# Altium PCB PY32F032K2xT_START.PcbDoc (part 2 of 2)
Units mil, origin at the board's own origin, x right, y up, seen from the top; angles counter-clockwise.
Board outline 1771.65 x 3929.06 mil, 2 copper layers (Top Layer, Bottom Layer), stack 21 mil thick; 140 components, 131 nets, 499 pads, 343 vias.
Unrouted connection lines stored in the file: 5.

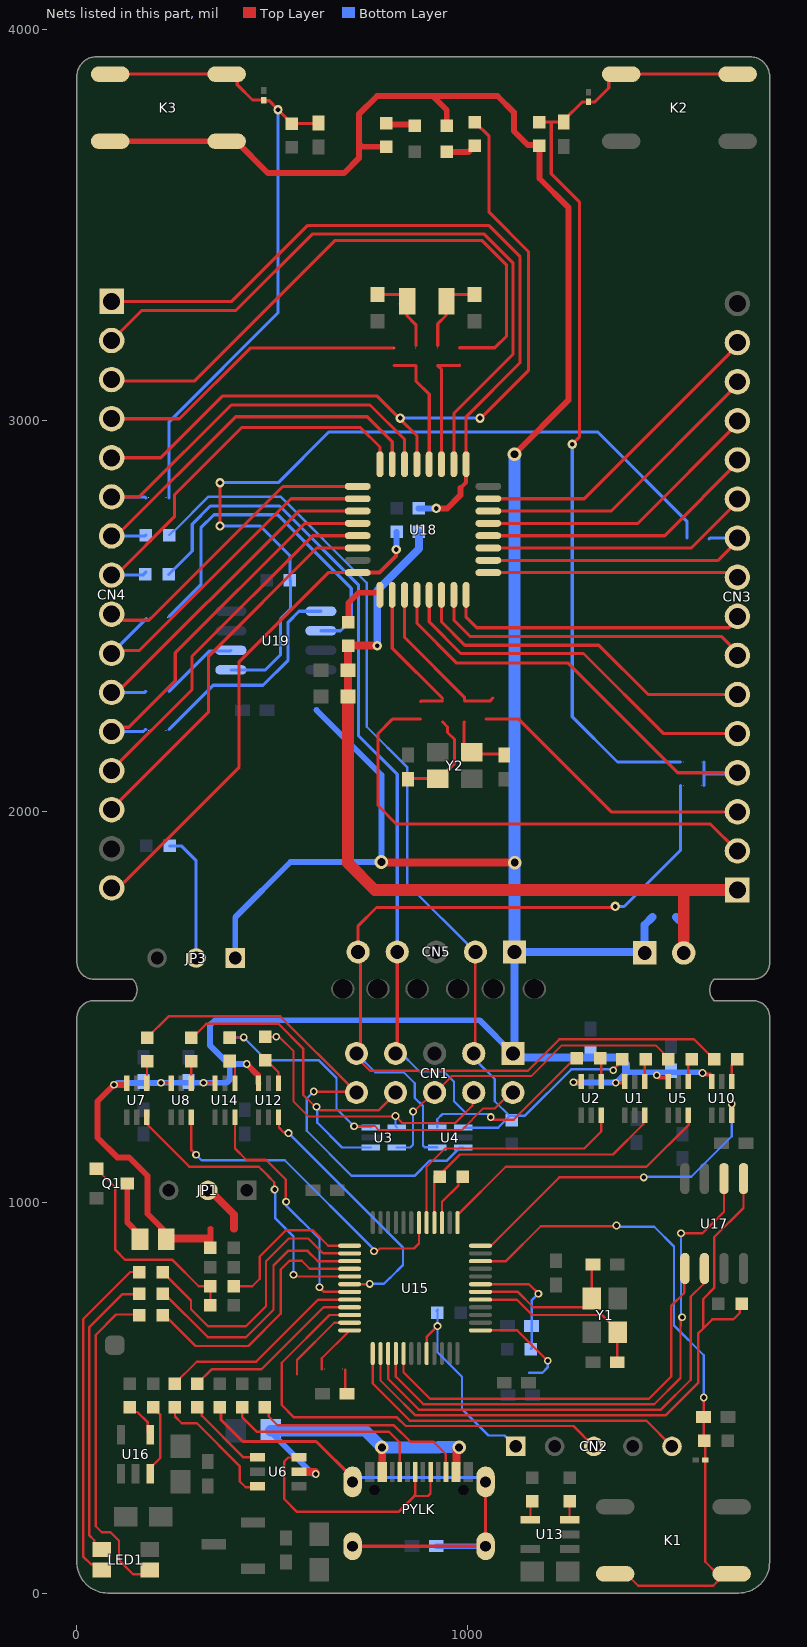
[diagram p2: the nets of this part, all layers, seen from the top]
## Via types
v1: diameter 24, hole 12, Top Layer to Bottom Layer, tented both sides, 162 vias
v2: diameter 19.68, hole 11.81, Top Layer to Bottom Layer, tented both sides, 128 vias
v3: diameter 19.68, hole 11.81, Top Layer to Bottom Layer, 38 vias
v4: diameter 35, hole 20, Top Layer to Bottom Layer, tented both sides, 11 vias
v5: diameter 30, hole 15, Top Layer to Bottom Layer, tented both sides, 2 vias
v6: diameter 40, hole 20, Top Layer to Bottom Layer, tented both sides, 2 vias

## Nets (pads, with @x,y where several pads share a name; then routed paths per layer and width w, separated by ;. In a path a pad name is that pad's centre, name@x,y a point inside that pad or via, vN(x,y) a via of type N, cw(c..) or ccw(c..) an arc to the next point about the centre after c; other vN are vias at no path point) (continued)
L_USB_CN_DP: PYLK.A6 PYLK.B6 U6.6 | length 662.8
  Top Layer w6: U6.6@568.15,347.4 567.26,346.51 540.39,346.51 530.35,336.47 530.35,240.4 563.22,207.53 822.27,207.53 863.1,248.36 865.36,250.62 PYLK.A6@865.36,309.89 ; 863.46,248 898,248 904.31,254.31 PYLK.B6@904.31,309.48
LED_BLUE: R9.2 U15.28 | length 675.2
  Top Layer w6: R9.2@220,710 225.04,710 303.26,631.77 438.53,631.77 521.33,714.58 521.33,827.41 543.92,850 575,850 595.79,829.21 U15.28@697.68,829.21
LED_GREEN: R6.2 U15.26 | length 724.3
  Top Layer w6: R6.2@220,820 291.82,748.18 291.82,725.67 335.36,682.13 432.27,682.13 483.48,733.34 483.48,848.48 541.75,906.75 591.91,906.75 630.07,868.58 U15.26@697.68,868.58
LED_RED: R4.2 U15.27 | length 692.2
  Top Layer w6: R4.2@220,765 224.07,765 335.03,654.04 432.13,654.04 502.68,724.59 502.68,837.68 540,875 590,875 616.1,848.9 U15.27@697.68,848.9
MCU_RST: CN3.4 R50.2 R57.2 U18.4 | length 1217.7
  Top Layer w8: U18.4@869.69,2558.46 869.69,2480.19 971.65,2378.23 1256.77,2378.23 1537,2098 CN3.4@1697,2098
  Bottom Layer w8: 1604,2065.5 1604,2095.38 ; 1604,2125.25 1604,2095.38 ; CN3.4@1697,2098 1694.38,2095.38 1604,2095.38
NetC1_2: C1.2 PYLK.1 PYLK.2 PYLK.3 PYLK.4 R8.1 | length 1421.6
  Top Layer w8: R8.1@365,475 368.29,471.71 368.29,443.87 424.64,387.52 611.97,387.52 705.12,294.37 PYLK.1@705.12,284.29 ; PYLK.3@705.12,119.73 PYLK.4@1045.28,119.73 PYLK.2@1045.28,284.29
  Bottom Layer w8: PYLK.1@716.04,295.21 PYLK.2@1034.36,295.21 ; C1.2@919,120 C1.2@919.27,119.73
  Bottom Layer w15: C1.2@919.27,119.73 PYLK.4@1045.28,119.73
  Bottom Layer w20: PYLK.1@705.12,284.29 PYLK.1@716.04,295.21 ; PYLK.2@1034.36,295.21 PYLK.2@1045.28,284.29
NetC17_2: C17.2 R31.2 | length 64.1
  Top Layer w6: 686.21,571.75 686.21,513.88 C17.2@690.59,509.5
NetC29_2: C29.2 K2.1 K2.2 R49.2 R50.1 U20.1 | length 2453.3
  Top Layer w8: R49.2@1182.49,3761.8 1182.7,3762 R49.2@1183,3762 C29.2@1245,3762 ; 1213.34,3761.8 1213.34,3629.85 1285.19,3558 1285.19,2956.19 v1(1267,2938) ; C29.2@1244.19,3765.19 1292.59,3813.59 1324.59,3813.59 1360.13,3849.13 1360.13,3870.21 1374.63,3884.7 K2.1@1392,3884.7 K2.2@1690,3884.7
  Bottom Layer w8: v1(1267,2938) 1267,2241 1382.75,2125.25 1544,2125.25
NetC30_2: C30.2 R51.1 Y2.3 | length 254.5
  Top Layer w8: C30.2@847.03,2081.4 848.56,2082.93 Y2.3@922.72,2082.93 926.65,2082.93 966.03,2122.31 966.03,2182.97 948,2201 948,2215.05 935.03,2228.03
NetC31_1: C31.1 R52.2 Y3.2 | length 182.1
  Top Layer w8: C31.1@769,3321.5 Y3.2@828.14,3321.5 ; Y3.2@827.14,3297.5 843.81,3280.83 843.81,3280 843.81,3267.21 867,3244.02 867,3191
NetC32_2: C32.2 R53.2 Y3.1 | length 191.1
  Top Layer w8: 923,3191 923,3246.01 944.2,3267.21 944.2,3280 Y3.1@953.94,3289.75 ; Y3.1@945.2,3304 945.2,3304.83 961.87,3321.5 C32.2@1017,3321.5
NetC33_2: C33.2 R54.1 Y2.1 | length 173.1
  Top Layer w8: 991.03,2228.03 989.84,2226.84 989.84,2169.36 1013.43,2145.77 1090.65,2145.77 C33.2@1093.03,2143.4
NetC34_2: C34.2 K3.3 K3.4 R59.1 R60.2 U21.1 | length 1703.1
  Top Layer w8: K3.4@85,3884.7 K3.3@383,3884.7 395.51,3884.7 410,3870.21 410,3857.7 449.24,3818.46 477.83,3818.46 479.74,3816.54 491.81,3816.54 v1(514.4,3793.95) 537,3771.35 537,3769.98 R60.2@549,3757.98 616.09,3757.98 C34.2@618,3759.89
  Bottom Layer w8: 235.99,2800.6 235.99,2995.9 514.4,3274.31 v1(514.4,3793.95)
NetCN3_2: CN3.2 R61.2 | length 1275.6
  Top Layer w8: R61.2@878.97,2234.97 806.97,2234.97 770,2198 770,2014 817,1967 1620.29,1967 CN3.2@1689.29,1898
NetCN3_3: CN3.3 R62.2 | length 740.5
  Top Layer w8: R62.2@1046.97,2234.97 1130.03,2234.97 1367,1998 CN3.3@1689.29,1998
NetCN4_3: CN4.3 R63.2 | length 1500.5
  Top Layer w8: CN4.3@89,3103.44 93.02,3099.42 300.42,3099.42 660.54,3459.54 1035.37,3459.54 1099,3395.9 1099,3215.06 1068.97,3185.03 R63.2@979.03,3185.03
NetCN4_4: CN4.4 R64.2 | length 796.8
  Top Layer w8: CN4.4@89,3003.44 262.44,3003.44 443.03,3184.03 R64.2@811.03,3184.03
NetJP3_2: JP3.2 R48.1 | length 332.8
  Bottom Layer w8: R48.1@237,1911 267.28,1911 305,1873.28 JP3.2@305,1624.13
NetLED1_2: LED1.2 R9.1 | length 846.1
  Top Layer w6: R9.1@160,710 157.67,712.33 100.33,712.33 48,660 48,171 63.8,155.2 85.86,155.2 107.53,133.53 107.53,84.16 143.82,47.87 175.08,47.87 LED1.2@186.02,58.82
NetLED1_3: LED1.3 R6.1 | length 884.3
  Top Layer w6: LED1.3@44.28,58.52 LED1.3@58.98,43.82 ; LED1.3@63.98,58.82 49.28,73.52 36.09,73.52 16,93.61 16,700.34 136.59,820.93 159.07,820.93 R6.1@160,820
NetLED1_4: LED1.4 R4.1 | length 755.1
  Top Layer w6: LED1.4@56.66,98.5 44.36,110.81 44.36,134.74 32,147.09 32,680.34 115.39,763.73 158.73,763.73 R4.1@160,765
NetLED_PA11_2: LED_PA11.2 R58.1 | length 78.7
  Top Layer w15: LED_PA11.2@946,3685.89 1001.89,3685.89 R58.1@1018,3702
NetLED_VDD*_1: LED_VDD*.1 R40.1 | length 75.5
  Top Layer w15: R40.1@791,3759 794,3756 861,3756 LED_VDD*.1@864,3753
NetPYLK_A5: PYLK.A5 R1.2 | length 530.3
  Top Layer w6: R1.2@422.49,474.99 422.49,449.82 459.51,412.79 797.58,412.79 825.99,384.38 PYLK.A5@825.99,309.89
NetPYLK_B5: PYLK.B5 R3.1 | length 566
  Top Layer w6: R3.1@480,475 490.31,464.69 490.31,452.34 513.85,428.8 811.11,428.8 852.66,387.24 911.55,387.24 943.17,355.62 943.17,310.82 PYLK.B5@944.1,309.89
NetQ1_1: Q1.1 R19.1 R20.2 | length 559
  Top Layer w6: Q1.1@50,1084.8 51.97,1084.8 63.72,1073.06 63.72,1071.23 98.46,1036.49 98.46,877.34 123.86,851.94 244.45,851.94 311.61,784.78 R19.1@341.53,784.78 ; R20.2@341.52,735.88 R19.1@341.52,784.77
NetQ1_3: Q1.3 R15.1 | length 166.5
  Top Layer w6: Q1.3@125.49,1044.15 Q1.3@128.74,1047.4 ; R15.1@161.54,905 R15.1@161.54,910.91
  Top Layer w15: Q1.3@128.74,1047.4 128.74,948.28 161.54,915.49 R15.1@161.54,905
NetR2_1: R2.1 U1.4 | length 57.9
  Top Layer w6: U1.4@1452.23,1308.31 1452.23,1362.02 R2.1@1455.21,1365
NetR7_1: R7.1 U2.4 | length 57.8
  Top Layer w6: R7.1@1338.06,1365 1340.8,1362.27 U2.4@1340.8,1308.31
NetR10_1: R10.1 U5.4 | length 60.3
  Top Layer w6: U5.4@1563.66,1308.31 1563.66,1356.3 R10.1@1572.35,1365
NetR11_1: R11.1 U6.3 | length 332.9
  Top Layer w6: R11.1@250,475 250.77,474.23 250.77,451.69 268.41,434.05 306.8,434.05 416.24,324.61 416.24,285.87 431.63,270.48 459.74,270.48 U6.3@461.53,272.28
NetR12_1: R12.1 U6.1 | length 227.7
  Top Layer w6: R12.1@308.75,480 319.15,469.6 319.15,453.68 426,346.83 U6.1@471.97,346.83
NetR13_1: R13.1 U7.4 | length 59
  Top Layer w6: R13.1@173.55,1360 179.14,1354.41 U7.4@179.14,1303.31
NetR14_1: R14.1 U8.4 | length 60.8
  Top Layer w6: R14.1@280.94,1360.02 R14.1@290.82,1350.14 ; U8.4@292.86,1303.31 R14.1@292.86,1350.12
NetR18_1: R18.1 U10.4 | length 62.7
  Top Layer w6: U10.4@1675.08,1308.31 1675.08,1350.59 R18.1@1689.49,1365
NetR22_1: R22.1 U12.4 | length 75.3
  Top Layer w6: R22.1@481.63,1362.11 485.62,1362.11 515.71,1332.03 U12.4@515.71,1303.31
NetR24_2: R24.2 U13.4 | length 49.6
  Top Layer w6: U13.4@1160,187.5 1160,230 R24.2@1165,235
NetR25_2: R25.2 U13.3 | length 47.5
  Top Layer w6: U13.3@1260,187.5 R25.2@1260,235
NetR26_1: R26.1 U14.4 | length 62.8
  Top Layer w6: R26.1@391.2,1360.7 404.28,1347.62 U14.4@404.28,1303.31
NetR27_2: R27.2 U15.1 | length 273.6
  Top Layer w6: U15.1@1032.32,671.73 1126.27,671.73 v3(1204,594)
  Bottom Layer w6: R27.2@1157.03,563.03 1190.03,563.03 1204,577 v3(1204,594)
NetR29_2: R29.2 U16.4 | length 96.1
  Top Layer w6: R29.2@135,475 147,463 154.44,463 181.5,435.94 181.5,411 U16.4@187.5,405
NetR30_2: R30.2 U16.3 | length 188.5
  Top Layer w6: U16.3@187.5,305 187.5,320 213.56,346.06 213.56,455.68 207,462.24 207,463 R30.2@195,475
NetR31_1: R31.1 U15.36 | length 129.6
  Top Layer w6: 626.21,571.75 626.21,600.26 U15.36@697.68,671.73
NetR33_1: R33.1 U15.35 | length 210.5
  Top Layer w6: R33.1@563,559.75 563,596 658.42,691.42 U15.35@697.68,691.42
NetR41_2: R41.2 U18.1 | length 141.2
  Top Layer w15: R41.2@694,2483 694,2532 720.46,2558.46 U18.1@775.19,2558.46
NetR43_1: R43.1 R44.2 U19.1 | length 2112.9
  Top Layer w8: v1(366,2729) v1(366,2840)
  Bottom Layer w8: v1(366,2729) 468.67,2729 545,2652.67 R43.1@545,2590 545.88,2589.12 545.88,2516.48 520.91,2491.51 520.91,2399.5 482.41,2361 U19.1@394,2361 ; v1(366,2840) 515,2840 644.46,2969.46 1332.02,2969.46 1559.97,2741.51 1559.97,2698.97
NetR45_2: R45.2 U19.2 | length 201.4
  Bottom Layer w8: 235.99,2305.99 339.55,2409.55 392.56,2409.55 U19.2@394,2411
NetR46_1: R46.1 U19.6 | length 906.3
  Bottom Layer w8: 236,2498 317,2579 317,2724.11 350.76,2757.86 513.27,2757.86 701.55,2569.58 701.55,2488.36 674.19,2461 U19.6@624,2461
NetR47_1: R47.1 U19.5 | length 570
  Bottom Layer w8: 236,2209 348.82,2321.82 476.11,2321.82 540.16,2385.88 540.16,2483.09 568.08,2511 U19.5@624,2511
OSC32IN: R52.1 R64.1 U18.20 | length 328.1
  Top Layer w8: R64.1@811,3139.25 R52.1@867,3139.25 867,3100 901.09,3065.91 U18.20@901.09,2881.26
OSC32OUT: R53.1 R63.1 U18.19 | length 318.4
  Top Layer w8: U18.19@932.59,2881.26 932.59,3129.66 R53.1@923,3139.25 978,3139.25 R63.1@979,3140.25
OSCIN: R51.2 R61.1 U18.2 | length 380.2
  Top Layer w8: U18.2@806.69,2558.46 806.69,2416.36 935.03,2288.03 ; R61.1@879,2279.75 880.31,2281.05 R51.2@935.05,2281.05
OSCOUT: R54.2 R62.1 U18.3 | length 417
  Top Layer w8: U18.3@838.19,2558.46 838.19,2443.81 991.05,2290.95 R54.2@991.05,2281.05 1056.05,2281.05 1064,2289
PA0: CN3.6 U18.6 | length 916
  Top Layer w8: U18.6@932.59,2558.46 932.59,2483.79 992.38,2424 1335,2424 1461,2298 CN3.6@1697,2298
PA1: CN3.7 U18.7 | length 840.3
  Top Layer w8: U18.7@964.09,2558.46 964.09,2488.64 1006.73,2446 1649,2446 CN3.7@1697,2398
PA2: CN3.8 U18.8 | length 787.4
  Top Layer w8: U18.8@995.59,2558.46 995.59,2495.58 1022.27,2468.91 1667.91,2468.91 CN3.8@1697,2498
PA3: CN3.9 U18.9 | length 647.3
  Top Layer w8: U18.9@1046.79,2609.66 1662.22,2609.66 1673.88,2598 CN3.9@1689.29,2598
PA4: CN3.10 R44.1 U18.10 | length 754.6
  Top Layer w8: U18.10@1046.79,2641.16 1640.16,2641.16 CN3.10@1697,2698
  Bottom Layer w8: 1617,2696 1619,2698 CN3.10@1697,2698
PA5: CN3.11 U18.11 | length 702.1
  Top Layer w8: U18.11@1046.79,2672.66 1571.66,2672.66 CN3.11@1697,2798
PA6: CN3.12 U18.12 | length 730.5
  Top Layer w8: U18.12@1046.79,2704.16 1503.16,2704.16 CN3.12@1697,2898
PA7: CN3.13 U18.13 | length 758.9
  Top Layer w8: U18.13@1046.79,2735.56 1434.56,2735.56 CN3.13@1697,2998
PA8: CN4.2 U18.18 | length 1752.7
  Top Layer w8: CN4.2@89,3203.44 165.56,3280 406.46,3280 602,3475.54 1041.99,3475.54 1115,3402.52 1115,3167.74 964.09,3016.83 U18.18@964.09,2881.26
PA11: CN4.5 R58.2 U18.21 | length 2036.7
  Top Layer w8: CN4.5@89,2903.44 214.46,2903.44 372.21,3061.19 768.15,3061.19 825.67,3003.67 869.69,2959.65 U18.21@869.69,2881.26 ; R58.2@1018,3762 1054.38,3725.62 1054.38,3531.39 1154.74,3431.03 1154.74,3126.47 1033.27,3005 v1(1030.96,3005)
  Bottom Layer w8: v1(827,3005) v1(1030.96,3005)
PA12: CN4.6 R59.2 U18.22 | length 1041.1
  Top Layer w8: CN4.6@89,2803.44 159.8,2803.44 394.97,3038.61 749.67,3038.61 838.19,2950.09 U18.22@838.19,2881.26
  Bottom Layer w8: CN4.6@89.56,2804 CN4.6@89,2803.44 173.15,2803.44 175.99,2800.6
PA15: CN4.9 U18.25 | length 783.2
  Top Layer w8: CN4.9@89,2503.44 104.41,2503.44 120.04,2487.82 184.42,2487.82 526.66,2830.06 U18.25@723.99,2830.06
PB0: CN3.14 U18.14 | length 787.3
  Top Layer w8: U18.14@1046.79,2767.06 1366.06,2767.06 CN3.14@1697,3098
PB1: CN3.15 U18.15 | length 815.7
  Top Layer w8: U18.15@1046.79,2798.56 1297.56,2798.56 CN3.15@1697,3198
PB3: CN4.10 R46.2 U18.26 | length 925.1
  Top Layer w8: CN4.10@89,2403.44 96.54,2410.98 160.12,2410.98 547.71,2798.56 U18.26@723.99,2798.56
  Bottom Layer w8: CN4.10@89,2403.44 178.41,2492.85
PB4: CN4.11 R45.1 U18.27 | length 915.1
  Top Layer w8: CN4.11@89,2303.44 103.66,2303.44 567.27,2767.06 U18.27@723.99,2767.06
  Bottom Layer w8: CN4.11@89,2303.44 173.44,2303.44 175.99,2305.99
PB5: CN4.12 R47.2 U18.28 | length 986.6
  Top Layer w8: CN4.12@89,2203.44 99.9,2214.34 132.93,2214.34 251.59,2333.01 251.59,2404.46 582.69,2735.56 U18.28@723.99,2735.56
  Bottom Layer w8: CN4.12@89,2203.44 170.44,2203.44 176,2209
PB6: CN4.13 U18.29 | length 934.6
  Top Layer w8: CN4.13@89,2103.44 89,2105.19 294.4,2310.6 294.4,2395.6 602.96,2704.16 U18.29@723.99,2704.16
PB7: CN4.14 U18.30 | length 997
  Top Layer w8: CN4.14@89,2003.44 89,2006.06 336.87,2253.92 336.87,2396.13 613.4,2672.66 U18.30@723.99,2672.66
PF3: CN3.5 U18.5 | length 988.9
  Top Layer w8: U18.5@901.09,2558.46 901.09,2483.95 982.04,2403 1295.78,2403 1500.78,2198 CN3.5@1697,2198
PYLK_BOOT0: CN2.1 R28.1 U15.44 | length 539.6
  Top Layer w6: U15.44@894.53,612.68 894.53,655.07 v2(922.21,682.75)
  Bottom Layer w6: R28.1@923.26,724.4 920.49,721.63 922.21,719.9 v2(922.21,682.75) 922.21,615.79 985,553 985,471 1053,403 1094,403 CN2.1@1122,375
PYLK_KEY: C6.2 K1.1 K1.2 R16.1 U11.1 U15.10 | length 1778.9
  Top Layer w6: U15.10@1032.32,848.9 1097.14,848.9 1186.44,938.2 1378.2,938.2 v2(1380,940) ; K1.2@1376.55,49 1405.25,49 1435.5,18.75 1627.36,18.75 1639.02,30.41 1639.02,34.51 K1.1@1653.51,49 ; v2(1603,500) C6.2@1603,450 1603,392 R16.1@1605,390 1607.3,387.7 U11.1@1607.3,340 1607.3,80 1638.3,49 K1.1@1653.51,49 ; K1.1@1674.55,49 K1.1@1653.51,49
  Bottom Layer w6: v2(1380,940) 1383.06,936.94 1392.62,936.94 1392.69,936.88 1476.64,936.88 1527,886.52 1527,684 1603,608 v2(1603,500)
PYLK_NRST: C24.2 R36.1 U15.7 | length 312.4
  Top Layer w6: U15.7@1032.32,789.84 1156.36,789.84 v2(1180.4,765.8)
  Bottom Layer w6: R36.1@1161,624 1163,626 C24.2@1163,683 1163,748.4 v2(1180.4,765.8) v2@1175.92,765.8
PYLK_OSCIN: C19.2 U15.5 Y1.3 | length 465.6
  Top Layer w6: U15.5@1032.32,750.47 1125.05,750.47 1164.42,711.1 1343.11,711.1 1383.59,670.63 Y1.3@1383.59,666.69 1382.12,665.22 C19.2@1382.12,590
PYLK_OSCOUT: C25.2 U15.6 Y1.1 | length 399.8
  Top Layer w6: U15.6@1032.32,770.16 1127.99,770.16 1167.36,730.79 1297.03,730.79 1316.66,750.41 Y1.1@1316.66,753.31 1316.66,836.54 C25.2@1320.12,840
PYLK_SPI_CS: R35.1 U15.38 U17.1 | length 1658.5
  Top Layer w5: U15.38@776.42,612.68 776.42,543.62 837.66,482.38
  Top Layer w6: 837.66,482.38 865.04,455 1506.42,455 1588.88,537.47 1588.88,663.88 1601.77,676.77 ; R35.1@1700,740 1695.62,735.62 1695.62,716.69 1679.36,700.42 1625.42,700.42 1601.77,676.77 ; U17.1@1705,1060 1705,985 1629.69,909.69 1629.69,780.01 1601.77,752.09 1601.77,676.77
PYLK_SPI_MISO: U15.40 U17.2 | length 1434.8
  Top Layer w6: U15.40@815.79,612.68 815.79,553.3 886.09,483 1476.7,483 1543.9,550.2 1543.9,683.16 1544.33,683.59 1544.33,701.49 v2(1547.84,705) ; v2(1545,920) 1600,920 1655,975 U17.2@1655,1060
  Bottom Layer w6: v2(1545,920) 1545.18,919.82 1545.18,707.66 v2(1547.84,705)
PYLK_SPI_MOSI: U15.41 U17.5 | length 1074.9
  Top Layer w6: U15.41@835.47,612.68 835.47,564.49 902.96,497 1463.12,497 1520.53,554.41 1520.53,735.09 1553.13,767.69 1553.13,828.13 U17.5@1555,830
PYLK_SPI_SCK: U15.39 U17.6 | length 1202.5
  Top Layer w6: U15.39@796.1,612.68 796.1,547.36 856.32,487.14 874.46,469 1493.77,469 1570.21,545.44 1570.21,758.06 1601.94,789.79 1601.94,826.94 U17.6@1605,830
SWCLK: CN4.8 R56.2 U18.24 | length 1035.9
  Top Layer w8: CN4.8@89,2603.44 99.89,2603.44 250,2753.55 250,2809.7 421.25,2980.96 725.12,2980.96 775.19,2930.89 U18.24@775.19,2881.26
  Bottom Layer w8: CN4.8@89,2603.44 168.43,2603.44 R56.2@175.99,2611
SWD_SCK: CN2.5 U15.37 | length 908.8
  Top Layer w6: U15.37@756.73,612.68 756.73,535.75 851.48,441 1456,441 CN2.5@1522,375
SWD_SDA: CN2.3 U15.34 | length 1174.2
  Top Layer w6: U15.34@697.68,711.1 646.11,711.1 524.05,589.04 524.05,480.71 555.57,449.2 818.75,449.2 840.95,427 1270,427 CN2.3@1322,375
SWDIO: CN4.7 R55.2 U18.23 | length 1009.9
  Top Layer w8: CN4.7@100.89,2703.44 405.95,3008.51 742.68,3008.51 806.69,2944.49 U18.23@806.69,2881.26
  Bottom Layer w8: CN4.7@89,2703.44 173.63,2703.44 R55.2@175.99,2705.8
T_RESET: CN1.9 CN5.5 R18.2 R57.1 U4.4 | length 2776.1
  Top Layer w6: CN1.9@722.78,1362.78 750.2,1335.36 1152.91,1335.36 1233.99,1416.44 1578.06,1416.44 R18.2@1629.49,1365
  Top Layer w8: CN1.9@715,1380 724.77,1389.77 724.77,1409.98 725,1410.21 725,1633.82 CN5.5@719.26,1639.56 719.26,1706.26 766.33,1753.33 1374.33,1753.33 v1(1377,1756)
  Bottom Layer w6: CN1.9@715,1380 763.22,1331.78 836.02,1331.78 864.1,1303.69 864.1,1266.42 885.15,1245.37 885.15,1144.31 889.61,1139.85 921.09,1139.85 U4.4@921.54,1139.41
  Bottom Layer w8: CN1.9@715,1380 CN1.9@724.04,1389.04 ; v1(1377,1756) 1399.67,1756 1544,1900.33 1544,2065.5
T_RESETa: U10.3 U15.12 | length 870.1
  Top Layer w6: U15.12@1032.32,888.27 1058.79,888.27 1233.47,1062.96 1321.53,1062.96 v2(1449.91,1062.96) ; v2(1674.82,1250.7) 1675.08,1250.44 U10.3@1675.08,1221.69
  Bottom Layer w6: v2(1449.91,1062.96) 1451.65,1064.7 1571.4,1064.7 1674.82,1168.11 v2(1674.82,1250.7)
T_RTCK_DTRa: U5.3 U15.13 | length 731.2
  Top Layer w6: U15.13@973.27,947.32 973.27,966.57 1096.7,1090 1456.99,1090 1565.18,1198.19 1565.18,1220.16 U5.3@1563.66,1221.69
T_RTCK_VCP_DTR: CN1.6 R10.2 U3.5 | length 868.3
  Top Layer w5: v2(859.81,1231.67) 863.24,1231.67 911.57,1280 CN1.6@915,1280 916.63,1280 958.49,1321.86 1161.73,1321.86 1240.3,1400.44 1479.98,1400.44 1500.35,1380.07 1500.35,1377 R10.2@1512.35,1365
  Bottom Layer w6: U3.5@818.46,1139.41 852.51,1139.41 859.81,1146.71 v2(859.81,1231.67)
T_TCK_SWCLK: CN1.7 CN5.4 R7.2 R56.1 U4.5 | length 2651
  Top Layer w6: v2(1058.5,1217.32) 1065.14,1210.69 1116.96,1210.69 1271.28,1365 R7.2@1278.06,1365
  Top Layer w8: CN1.7@815,1380 819.26,1384.26 CN5.4@819.26,1639.56
  Bottom Layer w6: CN1.7@822.5,1387.5 875.47,1334.53 937.65,1334.53 964.6,1307.57 964.6,1257.54 997.14,1225 ; U4.5@921.54,1190.59 921.54,1211.54 935,1225 997.14,1225 ; v2(1058.5,1217.32) 1050.82,1225 997.14,1225
  Bottom Layer w8: R56.1@235,2605 295,2665 295,2733.84 341.31,2780.15 518.52,2780.15 719.83,2578.83 719.83,2193.34 819.26,2093.91 CN5.4@819.26,1639.56 ; CN1.7@815,1380 CN1.7@817.79,1382.79
T_TCK_SWCLKa: U2.3 U15.17 | length 668.1
  Top Layer w5: U15.17@894.53,947.32 894.53,1089.76 941.77,1137
  Top Layer w6: 941.77,1137 1047.62,1137 1297.43,1137 1341.41,1180.98 1341.41,1221.08 U2.3@1340.8,1221.69
T_TDI_VCP_TX: CN1.4 R22.2 U3.4 | length 783.1
  Top Layer w5: R22.2@481.63,1422.11 517.9,1422.11 554.54,1385.48 554.54,1256.62 592.29,1218.86 v2@815,1218.86 ; R22.2@481.63,1425.11 R22.2@483.13,1423.61 ; v2@815.02,1218.86 831.78,1202.11 967.76,1202.11 1011.56,1245.9 1011.56,1276.56 CN1.4@1015,1280
  Bottom Layer w5: v2@815.06,1219.94 815.06,1194 U3.4@818.46,1190.59
  other v2: 815,1220
  other v3: 509.96,1422.98
T_TDI_VCP_TXa: U12.3 U15.30 | length 672.4
  Top Layer w6: U12.3@515.71,1216.69 516.93,1215.47 516.93,1190.37 529.24,1178.06 539.56,1178.06 v2(541.31,1176.31) ; U15.30@697.68,789.84 748.02,789.84 v2(748.76,790.58)
  Bottom Layer w6: v2(541.31,1176.31) 834.09,883.53 834.09,838.92 801.56,806.38 800.71,806.38 784.91,790.58 v2(748.76,790.58)
T_TDO_SWO: CN1.10 R13.2 U4.3 | length 1333.3
  Top Layer w6: R13.2@179.66,1420.08 234.47,1474.9 520.1,1474.9 CN1.10@708.51,1286.49 ; v2(605.87,1282.75) 606.54,1282.08 704.1,1282.08 CN1.10@708.51,1286.49 ; CN1.10@715,1280 CN1.10@708.51,1286.49
  Bottom Layer w6: v2(605.87,1282.75) 587.83,1264.72 587.83,1182.08 703.06,1066.86 863.29,1066.86 902.42,1105.99 946.45,1105.99 979.88,1139.41 U4.3@988.46,1139.41 U4.3@986.15,1137.1
T_TDO_SWOa: U7.3 U15.29 | length 807.7
  Top Layer w6: U7.3@179.14,1216.69 179.14,1198.86 287.46,1090.54 465.08,1090.54 471.63,1084 472.01,1084 489,1067.01 489,1066.63 504.93,1050.7 504.93,1032.69 v2(505.62,1032) ; v2(553.88,814.33) 558.68,809.53 641.55,809.53 U15.29@697.68,809.53
  Bottom Layer w6: v2(505.62,1032) 506.95,1030.68 506.95,958.93 553.88,912 v2(553.88,814.33)
T_TMS_SWDIO: CN1.3 CN5.2 R2.2 R5.2 R55.1 U4.1 | length 2629
  Top Layer w6: CN1.3@1015,1380 1019.26,1384.26 CN5.2@1019.26,1639.56 ; CN1.3@1019.37,1366.19 CN1.3@1025.56,1360 ; v2@1371.62,1338.31 1382.21,1348.9 1382.21,1352 R2.2@1395.21,1365
  Bottom Layer w6: R55.1@235.99,2705.8 248.99,2718.8 251.32,2718.8 336.62,2804.1 520.62,2804.1 741.22,2583.5 741.22,2215.77 844.64,2112.35 844.64,1814.18 CN5.2@1019.26,1639.56 ; U4.1@988.77,1190.29 1077.45,1190.29 R5.2@1108.1,1220.94 ; CN1.3@1015,1380 CN1.3@1019,1384 ; CN1.3@1023.59,1359.7 1068.86,1314.42 1068.86,1257.89 1105.81,1220.94 R5.2@1108.1,1220.94 ; v2(1371.43,1337.07) 1369.25,1339.25 1264.29,1339.25 1145.98,1220.94 R5.2@1108.1,1220.94
T_TMS_SWDIOa: R32.1 U1.3 U15.16 | length 723.8
  Top Layer w6: U15.16@914.21,947.32 R32.1@914.21,1067.37 ; R32.1@927.46,1064.37 927.46,1068.99 980.12,1121.65 1036.7,1121.65 1371.22,1121.65 1448.34,1198.77 1448.34,1217.8 U1.3@1452.23,1221.69
T_TMS_SWDIOa_OUT: R32.2 U15.15 | length 143.2
  Top Layer w6: U15.15@933.9,947.32 933.9,1000.64 975.82,1042.56 R32.2@975.82,1073.16
T_TRST_RTSa: U8.3 U15.18 | length 840.3
  Top Layer w6: U8.3@292.86,1216.69 292.86,1132.86 v2(304.82,1120.9) ; v2(759.92,874.35) 763.83,870.44 774.54,881.16 862.39,881.16 874.84,893.6 U15.18@874.84,947.32
  Bottom Layer w6: v2(304.82,1120.9) 318.81,1106.91 531.65,1106.91 759.92,878.64 v2(759.92,874.35)
T_TRST_VCP_RTS: CN1.8 R14.2 U3.1 | length 935
  Top Layer w6: R14.2@292.3,1420.1 295.54,1420.1 331.24,1455.8 515.25,1455.8 578.58,1392.47 578.58,1274.56 609.4,1243.73 v2(612.86,1243.73) 621.6,1235 772.67,1235 820,1282.33 CN1.8@820,1290
  Bottom Layer w6: v2(612.86,1243.73) 615,1241.6 615,1202.6 678.19,1139.41 U3.1@751.54,1139.41
T_VCP_RX: CN1.2 R23.1 R26.2 U3.3 | length 1000.9
  Top Layer w5: v2(708.97,1193.74) 710.23,1195 761.42,1195 772.45,1183.97 983.91,1183.97 1039.3,1239.36 1069.36,1239.36 CN1.2@1120,1290
  Top Layer w6: R26.2@391.2,1420.7 426.7,1420.7 v3(427,1421) ; R26.2@391.2,1431.85 R26.2@391.32,1431.97
  Bottom Layer w6: R23.1@391,1420 392,1421 v3(427,1421) 485.72,1362.28 619.26,1362.28 664.05,1317.5 664.05,1238.66 v2(708.97,1193.74) 708.23,1193 708.23,1191.77 750.36,1191.77 U3.3@751.54,1190.59
T_VCP_RXa: U14.3 U15.31 | length 636
  Top Layer w6: U14.3@404.28,1216.69 404.28,1137.29 433.27,1108.3 483.54,1108.3 534.4,1057.43 534.4,1001.38 v2(535,1000.78) ; v2(620.4,781.75) 631.99,770.16 U15.31@697.68,770.16
  Bottom Layer w6: v2(535,1000.78) 535,991.42 620.4,906.02 v2(620.4,781.75)
TVDD: C12.2 C13.2 C14.2 C15.2 CN1.1 CN5.1 JP2.1 JP3.1 K3.1 K3.2 LED_PA11.1 R15.2 R17.2 R23.2 R34.2 R39.1 R40.2 R42.2 R49.1 U1.6 U2.6 U5.6 U7.6 U8.6 U10.6 U12.6 U14.6 | length 8640.3
  Top Layer w6: U8.6@241.67,1303.31 U8.6@244.56,1306.2 ; U14.6@353.1,1303.31 U14.6@355.99,1306.2
  Top Layer w10: v2(215,1305) 239.98,1305 U8.6@241.67,1303.31 ; v3@325,1305 351.41,1305 U14.6@353.1,1303.31 ; v3(1377.88,1305.09) 1399.07,1305.09 1399.16,1305 1401.05,1306.89 U1.6@1401.05,1308.31 ; v2(1483.29,1324.06) 1488.61,1318.74 1512.47,1318.74 U5.6@1512.47,1308.31 ; v2@1608.68,1326.1 1618.91,1326.1 1623.9,1321.1 U10.6@1623.9,1308.31
  Top Layer w12: v2@1270.9,1306.9 U2.6@1289.01,1306.9
  Top Layer w15: K3.2@85,3713 K3.1@383,3713 407.27,3713 488.4,3631.87 683.55,3631.87 721.11,3669.43 721.11,3706.99 ; v2(95,1300) 52.5,1257.5 52.5,1164.78 103.07,1114.2 133.42,1114.2 180.53,1067.09 180.53,969.95 220.52,929.96 220.52,912.95 R15.2@228.46,905 R15.2@230.24,906.78 ; v2@95.63,1299.37 U7.6@127.35,1299.37 ; 338.07,906.78 342.08,902.77 ; R17.2@342.08,874.02 342.08,902.77 ; 342.08,931.52 342.08,902.77 ; v3(434.28,1353.05) 462.84,1324.49 462.84,1305 U12.6@464.53,1303.31 ; v4(778.66,1869.56) v4@779.44,1868.78 ; R40.2@791,3699 729.1,3699 721.11,3706.99 ; LED_PA11.1@946,3752.89 946,3792.79 909.79,3829 ; v4@1119.22,1868.78 v4(1120,1868) ; v4(1119.26,2912.74) 1257,3050.48 1257,3544 1183,3618 R49.1@1183,3702 1181.29,3703.71 1153.29,3703.71 1117.61,3739.39 1117.61,3787.39 1076,3829 909.79,3829 ; v2(1270,1306) v2@1270.9,1306.9 ; 721.11,3706.99 721.11,3782.11 768,3829 909.79,3829
  Top Layer w20: R15.2@230.24,906.78 338.07,906.78 ; v4@779.44,1868.78 v4@1119.22,1868.78
  Bottom Layer w15: v2(95,1300) 98.79,1300 103.67,1304.88 C15.2@168.87,1304.88 ; C15.2@170,1303.74 C15.2@168.87,1304.88 ; v2@214.88,1304.88 C15.2@168.87,1304.88 ; v2(215,1305) v3(323.77,1305) 383,1305 391,1313 R23.2@391,1353.05 ; JP3.1@405,1624.13 405,1728 546.56,1869.56 v4(778.66,1869.56) 778.66,2092.34 613,2258 ; v3(434.28,1353.05) R23.2@391,1353.05 ; CN1.1@1115,1380 1030,1465 353,1465 340,1452 340,1400.76 380.76,1360 R23.2@391,1360 R23.2@391,1353.05 ; v2@1270.38,1305.62 v3@1377.36,1305.62 ; v3(1377.88,1305.09) 1379.15,1305.09 1381.49,1307.43 1382.09,1307.43 1406.58,1331.92 ; 1404.72,1331.92 1406.58,1331.92 ; v2(1600,1330) 1598.08,1331.92 1406.58,1331.92
  Bottom Layer w20: CN1.1@1118.94,1383.94 CN5.1@1118.94,1639.24 ; CN5.1@1119.26,1639.56 1449.44,1639.56 JP2.1@1452,1637 1452,1709 1472,1729 ; CN1.1@1122.04,1388.26 1143.46,1370 1386.9,1370 1404.72,1352.18 1404.72,1331.92
  Bottom Layer w30: v4@1118,2914 v4(1119.26,2912.74) CN5.1@1119.26,1639.56
TVDD*: JP1.2 R34.1 | length 129
  Top Layer w20: JP1.2@335,1030 339.73,1030 402.08,967.65 402.08,931.52
TVDD_DISCHARGE_EN: R19.2 U15.25 | length 404.9
  Top Layer w6: R19.2@401.53,784.78 448.51,784.78 467.48,803.75 467.48,860.55 534.58,927.66 603.61,927.66 643,888.27 U15.25@697.68,888.27
USB_DM: R11.2 U15.32 | length 536.9
  Top Layer w6: R11.2@250,535 306.4,591.4 458.28,591.4 617.36,750.47 U15.32@697.68,750.47
USB_DP: R12.2 U15.33 | length 471.3
  Top Layer w6: R12.2@307.5,535 344.45,571.95 471.73,571.95 630.56,730.79 U15.33@697.68,730.79
VBUS_PYLK: F1.1 PYLK.A4 PYLK.A9 PYLK.B4 PYLK.B9 U6.5 | length 805.4
  Top Layer w10: PYLK.A4@774.81,309.89 PYLK.B9@786.62,309.89 ; PYLK.B4@963.78,309.88 PYLK.A9@975.6,309.88
  Top Layer w20: U6.5@568.15,310 568.98,309.17 609.58,309.17 v2@610.2,308.55 ; PYLK.B9@781.05,327.56 v4@781.05,371.45 ; PYLK.A9@971,331.66 v4@971,365.47
  Bottom Layer w15: F1.1@495.98,415 495.98,411.75 602.28,305.45 610.31,305.45 v2(611.2,304.55)
  Bottom Layer w20: v4@977.13,372.01 v4(977.62,372.5)
  Bottom Layer w30: F1.1@495.98,415 737.5,415 v4(780,372.5) ; v4@780.49,372.01 925.68,372.01 ; 925.68,373.41 v4@976.72,373.41
VCC/PB2: CN4.1 R38.1 U18.17 | length 1956.8
  Top Layer w8: CN4.1@89,3303.44 396.08,3303.44 590.64,3498 1053,3498 1133.75,3417.25 1133.75,3147.01 995.59,3008.86 U18.17@995.59,2881.26
  Top Layer w10: 980.83,2826.59 994.86,2840.62 994.86,2880.53 U18.17@995.59,2881.26
  Top Layer w15: v1(919,2774) 947.28,2774 980.83,2807.55 980.83,2826.59
  Bottom Layer w8: R38.1@871,2777 R38.1@874,2774
  Bottom Layer w15: R38.1@874,2774 v1(919,2774)
VDD: C26.2 C27.2 CN3.1 JP2.2 R38.2 R39.2 R41.1 | length 2259
  Top Layer w20: C27.2@693.5,2293 C26.2@693.5,2360 693.75,2360.25 693.75,2422.75 R41.1@694,2423 v1(768,2423)
  Top Layer w30: C27.2@693.5,2293 693.5,1866.5 762,1798 1554,1798 ; JP2.2@1552,1637 1552,1796 1554,1798 ; CN3.1@1697,1798 1554,1798
  Bottom Layer w20: v1(768,2423) 768,2564 875.07,2671.07 R38.2@875.07,2712.93 ; 1532,1729 1552,1709 JP2.2@1552,1637
VSS/PB8: CN4.16 R37.1 U18.32 | length 1299.2
  Top Layer w8: CN4.16@89,1803.44 104.41,1803.44 119.24,1818.27 121.08,1818.27 415.03,2112.21 415.03,2381.95 642.74,2609.66 U18.32@723.99,2609.66
  Top Layer w10: U18.32@723.99,2609.66 773.45,2609.66 815.81,2652.01 815.81,2667.81 v1(817,2669)
  Bottom Layer w15: v1(817,2669) 817.5,2669.5 817.5,2713.5 R37.1@818,2714
pads on no net: PYLK. PYLK.A8 PYLK.B8 U15.42 U15.45

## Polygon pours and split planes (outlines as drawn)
GND on Bottom Layer "NONET_L-01_P-001" (solid, remove dead copper, pour order 3): 0,3929.06 1773.49,3929.06 1773.49,0 0,0
GND on Top Layer "NONET_L-01_P-001" (solid, remove dead copper, pour order 4): 0,3929.06 1773.49,3929.06 1773.49,0 0,0

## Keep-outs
Keep-Out Layer:
  lines w8: 0,78.74 ccw(c78.74,78.74) 78.74,0 1692.91,0 ccw(c1692.91,78.74) 1771.65,78.74 1771.65,1473.35 ccw(c1730,1473.35) 1730,1515 1630,1515 cw(c1657.5,1542.5) 1630,1570 1730,1570 ccw(c1730,1611.65) 1771.65,1611.65 1771.65,3855.75 1771.65,3879.06 ccw(c1721.65,3879.06) 1721.65,3929.06 1692.91,3929.06 78.74,3929.06 50,3929.06 ccw(c50,3879.06) 0,3879.06 0,3859.09 0,1615 ccw(c43.75,1613.75) 42.5,1570 142.5,1570 cw(c115,1542.5) 142.5,1515 42.5,1515 ccw(c43.75,1471.25) 0,1470 0,78.74 ; 215,1515 cw(c242.5,1542.5) 215,1570 565,1570 585,1570 cw(c557.5,1542.5) 585,1515 565,1515 215,1515 ; 1260,1515 cw(c1287.5,1542.5) 1260,1570 1280,1570 1560,1570 cw(c1532.5,1542.5) 1560,1515 1280,1515 1260,1515

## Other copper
Top Layer:
  pour cut-out: 239,2545 352.28,2658.28 424,2658.28 424,2264 239,2264
  pour cut-out: 1655,1370 1665,1370 1665,1360 1655,1360
  pour cut-out: 275,490 285,490 285,480 275,480
  pour cut-out: 275,525 285,525 285,515 275,515
  pour cut-out: 330,525 335.5,525 335.5,503 330,503
  pour cut-out: 330,490 340,490 340,480 330,480
  region net 5V_USB_CHGR: 385,235 395,245 420,245 465,200 510,200 530,180 660,180 660,120 515,120 515,140 490,165 435,165 400,200 385,215
  region net 3V3_PYLK: 240,315 290,315 310,295 355,295 360,290 360,250 345,235 345,165 362.5,147.5 355,140 293.39,140 293.39,153.49 305,165.1 305,230 280,255 240,255
  region net 3V3_PYLK: 1095,155 1105,165 1125,165 1135,155 1135,130 1140,125 1185,125 1190,120 1190,105 1185,100 1130,100 1095,135
  region net 3V3_USB_PYLK: 1227.5,120 1300,120 1315,135 1335,135 1345,125 1345,105 1330,90 1315,90 1290,65 1290,25 1225,25 1225,118.33
  pour cut-out: 390,495 400,495 400,485 390,485
  pour cut-out: 445,495 455,495 455,485 445,485
  pour cut-out: 1627.43,1037 1637.43,1037 1637.43,1027 1627.43,1027
  pour cut-out: 1675,1075 1685,1075 1685,1065 1675,1065

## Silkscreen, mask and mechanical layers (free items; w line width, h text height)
Top Overlay:
  drawing of 1057 lines, arcs and shapes, not listed
  text "NRST" at 1476.78,3615.64 h60
  text "USER_PA12" at 99,3608.66 h60
  text "16" at 1664,3366.54 h50
  text "17" at 67,3366 h50
  text "GND" at 1526,3287.52 h50
  text "VDD/B2" at 160,3284.53 h50
  text "B1" at 1526,3186.39 h50
  text "A8" at 159.96,3183.89 h50
  text "B0" at 1526,3086.87 h50
  text "A9" at 159.96,3083.77 h50
  text "PY32F032-START V2.1" at 738,3030.17 h65
  text "A7" at 1525.96,2987.92 h50
  text "A10" at 159.96,2983.66 h50
  text "2025-12" at 891.95,2961.47 h65
  text "A11" at 159.96,2884.08 h50
  text "A6" at 1525.96,2879.53 h50
  text "A12" at 159.96,2784.5 h50
  text "A5" at 1525.96,2779.94 h50
  text "A13" at 159.96,2684.39 h50
  text "A4" at 1525.96,2680.99 h50
  text "A14" at 159.96,2584.81 h50
  text "A3" at 1525.96,2580.93 h50
  text "A15" at 159.96,2484.7 h50
  text "A2" at 1525.96,2480.34 h50
  text "B3" at 160,2384.59 h50
  text "A1" at 1525.96,2381.92 h50
  text "B4" at 160,2285.12 h50
  text "A0" at 1525.96,2280.53 h50
  text "B5" at 160,2185.11 h50
  text "F3" at 1526,2180.94 h50
  text "B6" at 160,2085 h50
  text "F2" at 1526,2081.99 h50
  text "B7" at 160,1985.53 h50
  text "F1" at 1526,1981.39 h50
  text "F4" at 160,1886.05 h50
  text "F0" at 1526,1881.87 h50
  text "B8" at 160,1785.94 h50
  text "NC/VDD" at 1453,1783.54 h50
  text "VDD*" at 1100,1710.51 h45
  text "NRST" at 630,1710.48 h45
  text "SWC" at 760,1710.48 h45
  text "GND" at 870,1710.48 h45
  text "SWD" at 985,1710.48 h45
  text "VDD*" at 1377,1701 h45
  text "1" at 1697,1699 h50
  text "VDD" at 1507,1698 h45
  text "BOOT0" at 246,1685.54 h50
  text "GND" at 125,1684.54 h50
  text "VDD*" at 420,1685 h50
  text "32" at 55,1676.54 h50
  text "IDD" at 1607,1624 h50
  text "NRST" at 670,1445.43 h40
  text "SWC" at 790,1445.43 h40
  text "GND" at 896.86,1445.43 h40
  text "SWD" at 996.31,1445.43 h40
  text "VDD*" at 1090,1445.46 h40
  text "DTR" at 896.86,1175.88 h40
  text "TX" at 996.31,1175.88 h40
  text "RX" at 1090,1175.88 h40
  text "SWO" at 670,1175.43 h40
  text "RTS" at 790,1175.43 h40
  text "VDD_SEL" at 513,1079.99 h45
  text "5V" at 190,1075.64 h60
  text "3V3" at 410,1075.64 h60
  text "VDD*" at 265,1075 h60
  text "DIO" at 1337.46,423 h50 r90
  text "BT0" at 1137.18,422.44 h50 r90
  text "VDD" at 1239,422 h50 r90
  text "GND" at 1436.46,421 h50 r90
  text "CLK" at 1537.46,421 h50 r90
  text "PY-LINK OB V2.1" at 618,396.17 h65
Bottom Overlay:
Mechanical 1:
  lines w6: 215,1515 565,1515 585,1515 ; 215,1570 565,1570 585,1570 ; 1260,1515 1280,1515 1560,1515 ; 1260,1570 1280,1570 1560,1570
  lines w8: 0,0 ccw(c0,1) 1,1 1,3938.01 ; 215,1515 cw(c242.5,1542.5) 215,1570 ; 585,1515 ccw(c557.5,1542.5) 585,1570 ; 1260,1515 cw(c1287.5,1542.5) 1260,1570 ; 1560,1515 ccw(c1532.5,1542.5) 1560,1570

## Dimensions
1856.64,2.11 to 1850.64,3930.11 on Mechanical 1
42.5,1570 to 78.74,3929.06 on Mechanical 1
78.74,0 to -5,1505 on Mechanical 1
0,0 to 1770,-60 on Mechanical 1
